VERSION 5.8 ;
BUSBITCHARS "[]" ; DIVIDERCHAR "/" ;
UNITS DATABASE MICRONS 1000 ; END UNITS
MANUFACTURINGGRID 0.005 ;
LAYER metal1 TYPE ROUTING ; DIRECTION HORIZONTAL ; PITCH 0.2 ; WIDTH 0.2 ; SPACING 0.2 ; RESISTANCE RPERSQ 0.1 ; END metal1
SITE core CLASS CORE ; SIZE 1 BY 1 ; SYMMETRY Y ; END core
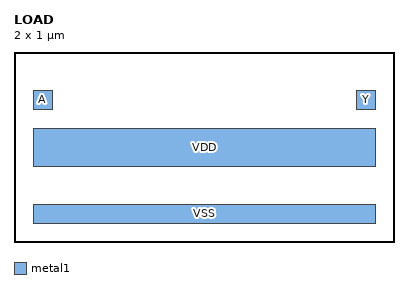
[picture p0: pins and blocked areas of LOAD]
MACRO LOAD CLASS CORE ; ORIGIN 0 0 ; SIZE 2 BY 1 ; SYMMETRY X Y ; SITE core ;
PIN VDD DIRECTION INOUT ; USE POWER ; PORT LAYER metal1 ; RECT 0.1 0.4 1.9 0.6 ; END END VDD
PIN VSS DIRECTION INOUT ; USE GROUND ; PORT LAYER metal1 ; RECT 0.1 0.1 1.9 0.2 ; END END VSS
PIN A DIRECTION INPUT ; USE SIGNAL ; PORT LAYER metal1 ; RECT 0.1 0.7 0.2 0.8 ; END END A
PIN Y DIRECTION OUTPUT ; USE SIGNAL ; PORT LAYER metal1 ; RECT 1.8 0.7 1.9 0.8 ; END END Y
END LOAD
END LIBRARY
